VERSION 5.7 ;
  NOWIREEXTENSIONATPIN ON ;
  DIVIDERCHAR "/" ;
  BUSBITCHARS "[]" ;
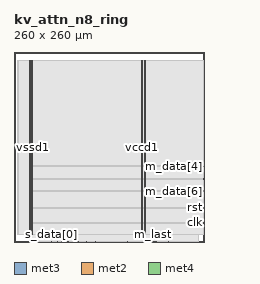
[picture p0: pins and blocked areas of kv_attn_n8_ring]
MACRO kv_attn_n8_ring
  CLASS BLOCK ;
  FOREIGN kv_attn_n8_ring ;
  ORIGIN 0.000 0.000 ;
  SIZE 260.000 BY 260.000 ;
  PIN clk
    DIRECTION INPUT ;
    USE SIGNAL ;
    ANTENNAGATEAREA 1.286700 ;
    ANTENNADIFFAREA 0.434700 ;
    PORT
      LAYER met3 ;
        RECT 259.400 25.880 260.000 26.480 ;
    END
  END clk
  PIN m_data[0]
    DIRECTION OUTPUT ;
    USE SIGNAL ;
    ANTENNADIFFAREA 0.702900 ;
    PORT
      LAYER met2 ;
        RECT 188.690 0.000 188.970 0.280 ;
    END
  END m_data[0]
  PIN m_data[1]
    DIRECTION OUTPUT ;
    USE SIGNAL ;
    ANTENNADIFFAREA 0.702900 ;
    PORT
      LAYER met2 ;
        RECT 155.570 0.000 155.850 0.280 ;
    END
  END m_data[1]
  PIN m_data[2]
    DIRECTION OUTPUT ;
    USE SIGNAL ;
    ANTENNADIFFAREA 0.702900 ;
    PORT
      LAYER met2 ;
        RECT 154.650 0.000 154.930 0.280 ;
    END
  END m_data[2]
  PIN m_data[3]
    DIRECTION OUTPUT ;
    USE SIGNAL ;
    ANTENNADIFFAREA 0.702900 ;
    PORT
      LAYER met2 ;
        RECT 194.210 0.000 194.490 0.280 ;
    END
  END m_data[3]
  PIN m_data[4]
    DIRECTION OUTPUT ;
    USE SIGNAL ;
    ANTENNADIFFAREA 0.702900 ;
    PORT
      LAYER met3 ;
        RECT 259.400 103.400 260.000 104.000 ;
    END
  END m_data[4]
  PIN m_data[5]
    DIRECTION OUTPUT ;
    USE SIGNAL ;
    ANTENNADIFFAREA 0.702900 ;
    PORT
      LAYER met2 ;
        RECT 211.690 0.000 211.970 0.280 ;
    END
  END m_data[5]
  PIN m_data[6]
    DIRECTION OUTPUT ;
    USE SIGNAL ;
    ANTENNADIFFAREA 0.702900 ;
    PORT
      LAYER met3 ;
        RECT 259.400 69.400 260.000 70.000 ;
    END
  END m_data[6]
  PIN m_data[7]
    DIRECTION OUTPUT ;
    USE SIGNAL ;
    ANTENNADIFFAREA 0.702900 ;
    PORT
      LAYER met3 ;
        RECT 259.400 85.720 260.000 86.320 ;
    END
  END m_data[7]
  PIN m_last
    DIRECTION OUTPUT ;
    USE SIGNAL ;
    ANTENNADIFFAREA 0.702900 ;
    PORT
      LAYER met2 ;
        RECT 189.610 0.000 189.890 0.280 ;
    END
  END m_last
  PIN m_ready
    DIRECTION INPUT ;
    USE SIGNAL ;
    ANTENNAGATEAREA 0.647700 ;
    ANTENNADIFFAREA 0.434700 ;
    PORT
      LAYER met2 ;
        RECT 190.530 0.000 190.810 0.280 ;
    END
  END m_ready
  PIN m_valid
    DIRECTION OUTPUT ;
    USE SIGNAL ;
    ANTENNADIFFAREA 0.702900 ;
    PORT
      LAYER met2 ;
        RECT 191.450 0.000 191.730 0.280 ;
    END
  END m_valid
  PIN rst
    DIRECTION INPUT ;
    USE SIGNAL ;
    ANTENNAGATEAREA 0.647700 ;
    ANTENNADIFFAREA 0.434700 ;
    PORT
      LAYER met3 ;
        RECT 259.400 46.280 260.000 46.880 ;
    END
  END rst
  PIN s_data[0]
    DIRECTION INPUT ;
    USE SIGNAL ;
    ANTENNAGATEAREA 0.647700 ;
    ANTENNADIFFAREA 0.434700 ;
    PORT
      LAYER met2 ;
        RECT 50.690 0.000 50.970 0.280 ;
    END
  END s_data[0]
  PIN s_data[1]
    DIRECTION INPUT ;
    USE SIGNAL ;
    ANTENNAGATEAREA 0.647700 ;
    ANTENNADIFFAREA 0.434700 ;
    PORT
      LAYER met2 ;
        RECT 87.490 0.000 87.770 0.280 ;
    END
  END s_data[1]
  PIN s_data[2]
    DIRECTION INPUT ;
    USE SIGNAL ;
    ANTENNAGATEAREA 0.647700 ;
    ANTENNADIFFAREA 0.434700 ;
    PORT
      LAYER met2 ;
        RECT 58.970 0.000 59.250 0.280 ;
    END
  END s_data[2]
  PIN s_data[3]
    DIRECTION INPUT ;
    USE SIGNAL ;
    ANTENNAGATEAREA 0.647700 ;
    ANTENNADIFFAREA 0.434700 ;
    PORT
      LAYER met2 ;
        RECT 73.690 0.000 73.970 0.280 ;
    END
  END s_data[3]
  PIN s_data[4]
    DIRECTION INPUT ;
    USE SIGNAL ;
    ANTENNAGATEAREA 0.647700 ;
    ANTENNADIFFAREA 0.434700 ;
    PORT
      LAYER met2 ;
        RECT 86.570 0.000 86.850 0.280 ;
    END
  END s_data[4]
  PIN s_data[5]
    DIRECTION INPUT ;
    USE SIGNAL ;
    ANTENNAGATEAREA 0.647700 ;
    ANTENNADIFFAREA 0.434700 ;
    PORT
      LAYER met2 ;
        RECT 111.410 0.000 111.690 0.280 ;
    END
  END s_data[5]
  PIN s_data[6]
    DIRECTION INPUT ;
    USE SIGNAL ;
    ANTENNAGATEAREA 0.647700 ;
    ANTENNADIFFAREA 0.434700 ;
    PORT
      LAYER met2 ;
        RECT 64.490 0.000 64.770 0.280 ;
    END
  END s_data[6]
  PIN s_data[7]
    DIRECTION INPUT ;
    USE SIGNAL ;
    ANTENNAGATEAREA 0.647700 ;
    ANTENNADIFFAREA 0.434700 ;
    PORT
      LAYER met2 ;
        RECT 99.450 0.000 99.730 0.280 ;
    END
  END s_data[7]
  PIN s_last
    DIRECTION INPUT ;
    USE SIGNAL ;
    ANTENNAGATEAREA 0.647700 ;
    ANTENNADIFFAREA 0.434700 ;
    PORT
      LAYER met2 ;
        RECT 185.930 0.000 186.210 0.280 ;
    END
  END s_last
  PIN s_ready
    DIRECTION OUTPUT ;
    USE SIGNAL ;
    ANTENNADIFFAREA 0.702900 ;
    PORT
      LAYER met2 ;
        RECT 187.770 0.000 188.050 0.280 ;
    END
  END s_ready
  PIN s_valid
    DIRECTION INPUT ;
    USE SIGNAL ;
    ANTENNAGATEAREA 0.647700 ;
    ANTENNADIFFAREA 0.434700 ;
    PORT
      LAYER met2 ;
        RECT 186.850 0.000 187.130 0.280 ;
    END
  END s_valid
  PIN vccd1
    DIRECTION INOUT ;
    USE POWER ;
    PORT
      LAYER met4 ;
        RECT 21.040 10.640 22.640 247.760 ;
    END
    PORT
      LAYER met4 ;
        RECT 174.640 10.640 176.240 247.760 ;
    END
  END vccd1
  PIN vssd1
    DIRECTION INOUT ;
    USE GROUND ;
    PORT
      LAYER met4 ;
        RECT 24.340 10.640 25.940 247.760 ;
    END
    PORT
      LAYER met4 ;
        RECT 177.940 10.640 179.540 247.760 ;
    END
  END vssd1
  OBS
      LAYER nwell ;
        RECT 5.330 10.795 254.570 247.710 ;
      LAYER li1 ;
        RECT 5.520 10.795 254.380 247.605 ;
      LAYER met1 ;
        RECT 5.520 10.640 254.380 247.760 ;
      LAYER met2 ;
        RECT 21.070 0.560 252.910 247.705 ;
        RECT 21.070 0.280 50.410 0.560 ;
        RECT 51.250 0.280 58.690 0.560 ;
        RECT 59.530 0.280 64.210 0.560 ;
        RECT 65.050 0.280 73.410 0.560 ;
        RECT 74.250 0.280 86.290 0.560 ;
        RECT 87.130 0.280 87.210 0.560 ;
        RECT 88.050 0.280 99.170 0.560 ;
        RECT 100.010 0.280 111.130 0.560 ;
        RECT 111.970 0.280 154.370 0.560 ;
        RECT 155.210 0.280 155.290 0.560 ;
        RECT 156.130 0.280 185.650 0.560 ;
        RECT 186.490 0.280 186.570 0.560 ;
        RECT 187.410 0.280 187.490 0.560 ;
        RECT 188.330 0.280 188.410 0.560 ;
        RECT 189.250 0.280 189.330 0.560 ;
        RECT 190.170 0.280 190.250 0.560 ;
        RECT 191.090 0.280 191.170 0.560 ;
        RECT 192.010 0.280 193.930 0.560 ;
        RECT 194.770 0.280 211.410 0.560 ;
        RECT 212.250 0.280 252.910 0.560 ;
      LAYER met3 ;
        RECT 21.050 104.400 259.400 247.685 ;
        RECT 21.050 103.000 259.000 104.400 ;
        RECT 21.050 86.720 259.400 103.000 ;
        RECT 21.050 85.320 259.000 86.720 ;
        RECT 21.050 70.400 259.400 85.320 ;
        RECT 21.050 69.000 259.000 70.400 ;
        RECT 21.050 47.280 259.400 69.000 ;
        RECT 21.050 45.880 259.000 47.280 ;
        RECT 21.050 26.880 259.400 45.880 ;
        RECT 21.050 25.480 259.000 26.880 ;
        RECT 21.050 10.715 259.400 25.480 ;
  END
END kv_attn_n8_ring
END LIBRARY

